VERSION 5.7 ;
  NOWIREEXTENSIONATPIN ON ;
  DIVIDERCHAR "/" ;
  BUSBITCHARS "[]" ;
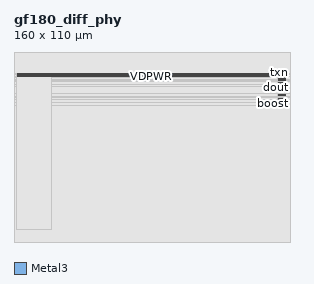
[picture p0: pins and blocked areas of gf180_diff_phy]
MACRO gf180_diff_phy
  CLASS BLOCK ;
  FOREIGN gf180_diff_phy ;
  ORIGIN 0.000 0.000 ;
  SIZE 160.000 BY 110.000 ;
  PIN din
    DIRECTION INPUT ;
    USE SIGNAL ;
    ANTENNAGATEAREA 3.920000 ;
    PORT
      LAYER Metal3 ;
        RECT 153.000 82.700 157.000 83.300 ;
    END
  END din
  PIN boost
    DIRECTION INPUT ;
    USE SIGNAL ;
    ANTENNAGATEAREA 10.639999 ;
    PORT
      LAYER Metal3 ;
        RECT 153.000 79.700 157.000 80.300 ;
    END
  END boost
  PIN rxp
    DIRECTION INPUT ;
    USE SIGNAL ;
    ANTENNAGATEAREA 24.000000 ;
    PORT
      LAYER Metal3 ;
        RECT 153.000 91.700 157.000 92.300 ;
    END
  END rxp
  PIN rxn
    DIRECTION INPUT ;
    USE SIGNAL ;
    ANTENNAGATEAREA 24.000000 ;
    PORT
      LAYER Metal3 ;
        RECT 153.000 90.700 157.000 91.300 ;
    END
  END rxn
  PIN txp
    DIRECTION OUTPUT ;
    USE SIGNAL ;
    PORT
      LAYER Metal3 ;
        RECT 153.000 94.700 157.000 95.300 ;
    END
  END txp
  PIN txn
    DIRECTION OUTPUT ;
    USE SIGNAL ;
    PORT
      LAYER Metal3 ;
        RECT 153.000 93.700 157.000 94.300 ;
    END
  END txn
  PIN dout
    DIRECTION OUTPUT ;
    USE SIGNAL ;
    ANTENNADIFFAREA 9.170000 ;
    PORT
      LAYER Metal3 ;
        RECT 153.000 84.700 157.000 85.300 ;
    END
  END dout
  PIN VDPWR
    DIRECTION INOUT ;
    USE POWER ;
    PORT
      LAYER Metal3 ;
        RECT 2.000 95.700 157.000 96.300 ;
    END
  END VDPWR
  PIN VGND
    DIRECTION INOUT ;
    USE GROUND ;
    PORT
      LAYER Metal3 ;
        RECT 2.000 96.700 157.000 97.300 ;
    END
  END VGND
  OBS
    LAYER Metal1 ;
      RECT 0.000 0.000 160.000 110.000 ;
    LAYER Metal2 ;
      RECT 0.000 0.000 160.000 110.000 ;
    LAYER Metal3 ;
      RECT 0.000 0.000 160.000 79.300 ;
      RECT 0.000 80.700 160.000 82.300 ;
      RECT 0.000 79.300 152.600 80.700 ;
      RECT 157.400 79.300 160.000 80.700 ;
      RECT 0.000 83.700 160.000 84.300 ;
      RECT 0.000 85.700 160.000 90.300 ;
      RECT 0.000 84.300 152.600 85.700 ;
      RECT 157.400 84.300 160.000 85.700 ;
      RECT 0.000 90.300 152.600 91.300 ;
      RECT 157.400 90.300 160.000 91.300 ;
      RECT 0.000 92.700 160.000 93.300 ;
      RECT 0.000 93.300 152.600 94.300 ;
      RECT 157.400 93.300 160.000 94.300 ;
      RECT 0.000 97.700 160.000 110.000 ;
      RECT 0.000 96.700 1.600 97.700 ;
      RECT 157.400 96.700 160.000 97.700 ;
      RECT 0.000 95.700 1.600 96.700 ;
      RECT 157.400 95.700 160.000 96.700 ;
      RECT 0.000 94.300 152.600 95.300 ;
      RECT 0.000 95.300 1.600 95.700 ;
      RECT 157.400 94.300 160.000 95.700 ;
      RECT 0.000 91.300 152.600 92.700 ;
      RECT 157.400 91.300 160.000 92.700 ;
      RECT 0.000 82.300 152.600 83.700 ;
      RECT 157.400 82.300 160.000 83.700 ;
    LAYER Metal4 ;
      RECT 1.400 7.400 21.600 97.600 ;
  END
END gf180_diff_phy
END LIBRARY

